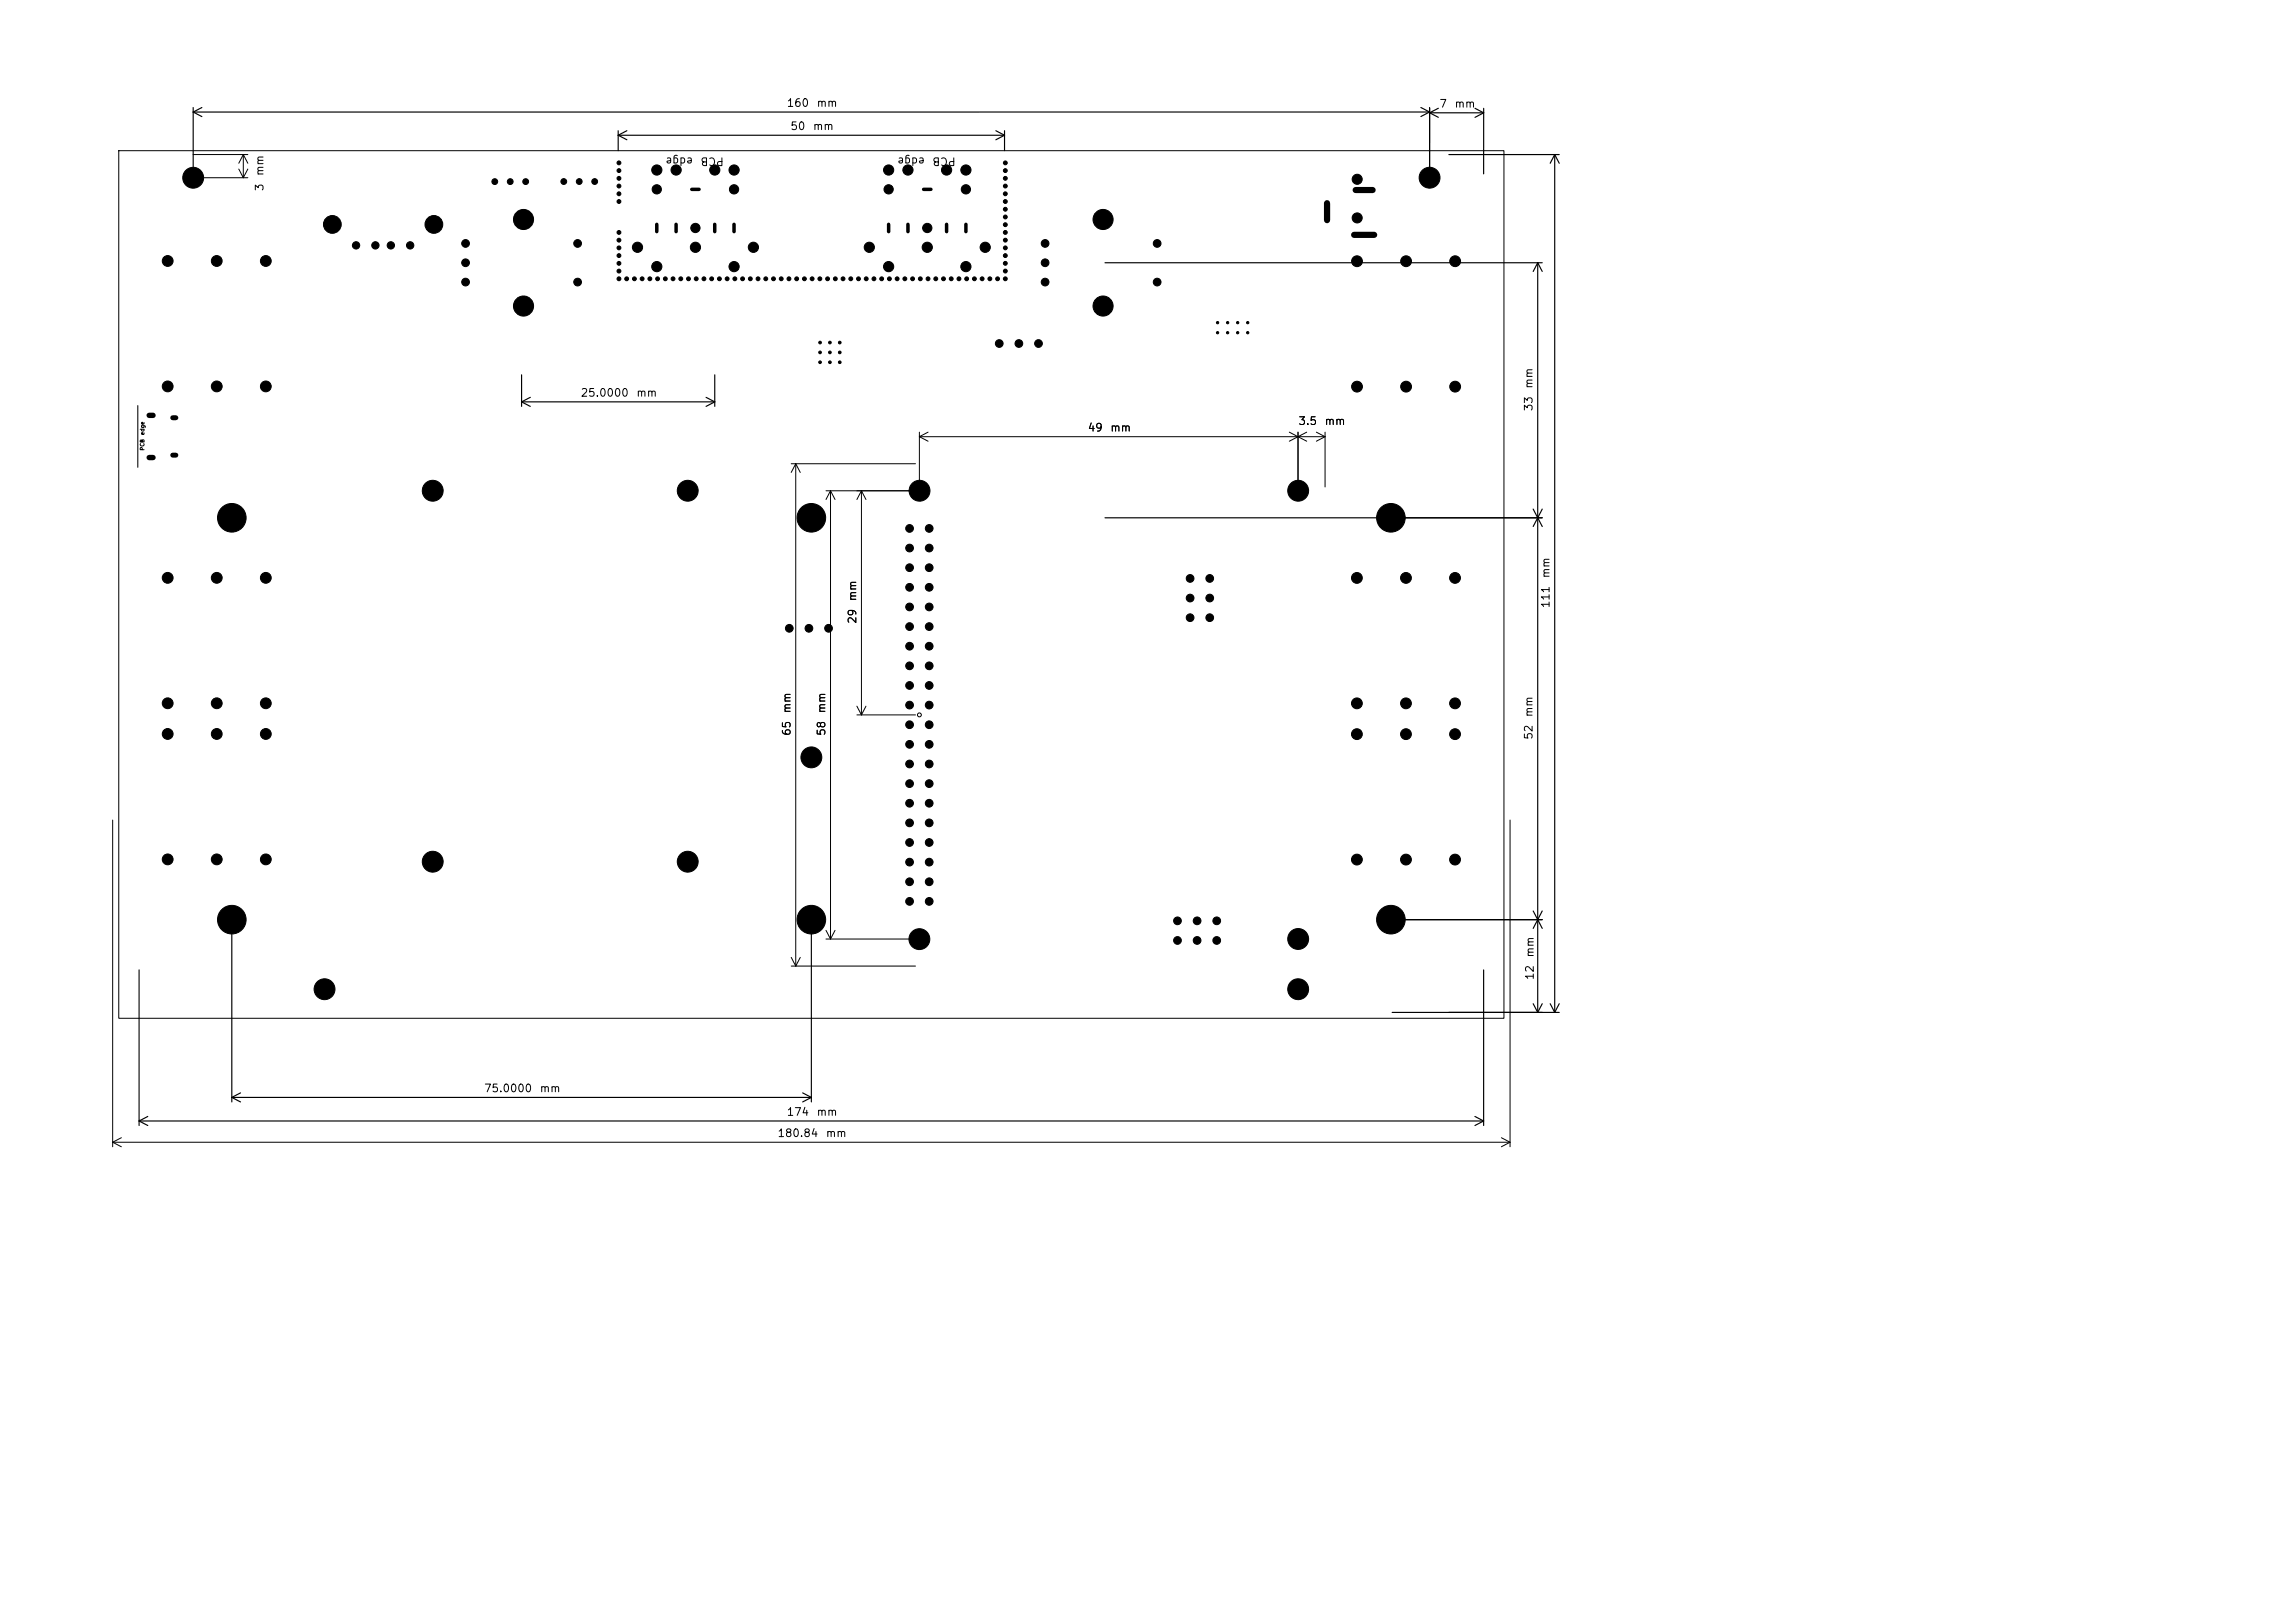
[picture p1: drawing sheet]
<svg xmlns="http://www.w3.org/2000/svg" width="297mm" height="210mm" viewBox="0 0 297 210" stroke-linecap="round" stroke-linejoin="round" font-family="sans-serif">
<defs><g id="words">
<g font-size="1">
<text x="101.7" y="14.1">160</text>
<text x="102.2" y="17.1">50</text>
<text x="105.1" y="17.1">mm</text>
<text x="105.6" y="14.1">mm</text>
<text x="186.2" y="14.2">7</text>
<text x="188.2" y="14.2">mm</text>
<text x="34.3" y="22.8" transform="rotate(-90 34.3 22.8)">mm</text>
<text x="89.8" y="20.1" transform="rotate(-180 89.8 20.1)">edge</text>
<text x="93.8" y="20.1" transform="rotate(-180 93.8 20.1)">PCB</text>
<text x="119.8" y="20.1" transform="rotate(-180 119.8 20.1)">edge</text>
<text x="123.8" y="20.1" transform="rotate(-180 123.8 20.1)">PCB</text>
<text x="34.3" y="24.8" transform="rotate(-90 34.3 24.8)">3</text>
<text x="75.1" y="51.6">25.0000</text>
<text x="82.3" y="51.6">mm</text>
<text x="198.6" y="53.3" transform="rotate(-90 198.6 53.3)">33</text>
<text x="198.6" y="50.4" transform="rotate(-90 198.6 50.4)">mm</text>
<text x="140.7" y="56.1">49</text>
<text x="143.6" y="56.1">mm</text>
<text x="168" y="55.2">3.5</text>
<text x="171.3" y="55.2">mm</text>
<text x="111.1" y="77.9" transform="rotate(-90 111.1 77.9)">mm</text>
<text x="200.8" y="74.9" transform="rotate(-90 200.8 74.9)">mm</text>
<text x="111.1" y="80.8" transform="rotate(-90 111.1 80.8)">29</text>
<text x="200.8" y="78.8" transform="rotate(-90 200.8 78.8)">111</text>
<text x="102.6" y="95.3" transform="rotate(-90 102.6 95.3)">65</text>
<text x="102.6" y="92.4" transform="rotate(-90 102.6 92.4)">mm</text>
<text x="107.1" y="95.3" transform="rotate(-90 107.1 95.3)">58</text>
<text x="107.1" y="92.4" transform="rotate(-90 107.1 92.4)">mm</text>
<text x="198.6" y="95.8" transform="rotate(-90 198.6 95.8)">52</text>
<text x="198.6" y="92.9" transform="rotate(-90 198.6 92.9)">mm</text>
<text x="198.7" y="124" transform="rotate(-90 198.7 124)">mm</text>
<text x="198.7" y="126.9" transform="rotate(-90 198.7 126.9)">12</text>
<text x="62.6" y="141.6">75.0000</text>
<text x="69.8" y="141.6">mm</text>
<text x="100.5" y="147.4">180.84</text>
<text x="101.7" y="144.6">174</text>
<text x="105.6" y="144.6">mm</text>
<text x="106.8" y="147.4">mm</text>
</g>
<g font-size=".5">
<text x="18.8" y="58.4" transform="rotate(-90 18.8 58.4)">PCB</text>
<text x="18.8" y="56.4" transform="rotate(-90 18.8 56.4)">edge</text>
</g>
</g></defs>
<g fill="none" stroke="#000" stroke-width=".13">
<path d="M15.4 19.5h179.2v112.3h-179.2zM25 20h7.1M31.5 20v3M31.5 20l.6 1.1M31.5 20l-.6 1.1M25 23h7.1M30.9 21.9l.6 1.1M32.1 21.9l-.6 1.1M17.8 52.5v8M119 55.9v7.1M119 56.5h52.5M119 56.5l1.1 .6"/>
<path d="M120.1 55.9l-1.1 .6M166.9 55.9l2.2 1.2M168 55.9v7.1M169.1 55.9l-2.2 1.2M170.4 55.9l1.1 .6M171.5 55.9v7.1M171.5 56.5l-1.1 .6M102.4 60h16.1M103 60v65M103 60l.6 1.1M103 60l-.6 1.1M106.9 63.5h11.6"/>
<path d="M107.5 63.5v58M107.5 63.5l.6 1.1M107.5 63.5l-.6 1.1M111.5 63.5v29M111.5 63.5l.6 1.1M111.5 63.5l-.6 1.1M110.9 92.5h7.6M110.9 91.4l.6 1.1M112.1 91.4l-.6 1.1M14.6 106.1v42.3M195.4 106.1v42.3M102.4 125h16.1"/>
<path d="M102.4 123.9l.6 1.1M103.6 123.9l-.6 1.1M106.9 121.5h11.6M106.9 120.4l.6 1.1M108.1 120.4l-.6 1.1M14.6 147.8h180.8M14.6 147.8l1.1 .6M15.7 147.2l-1.1 .6M194.3 147.2l1.1 .6M195.4 147.8l-1.1 .6"/>
<circle cx="119" cy="92.5" r=".25"/>
</g>
<g fill="none" stroke="#000" stroke-width=".15">
<path d="M25 13.9v8.6M25 14.5l1.1 .6M26.1 13.9l-1.1 .6M80 16.9v2.6M80 17.5h50M80 17.5l1.1 .6M81.1 16.9l-1.1 .6M128.9 16.9l1.1 .6M130 16.9v2.6M130 17.5l-1.1 .6M183.9 13.9l1.1 .6M185 13.9v8.6"/>
<path d="M185 14.5h-160M185 14.5l-1.1 .6M185 14.6h7M185 14.6l1.1 .6M186.1 14l-1.1 .6M190.9 14l1.1 .6M192 14.6l-1.1 .6M192 14v8.5M143 34h56.6M187.5 20h14.3M199 34v97M199 34l.6 1.1"/>
<path d="M199 34l-.6 1.1M201.2 20v111M201.2 20l.6 1.1M201.2 20l-.6 1.1M67.5 48.5v4.1M67.5 52h25M67.5 52l1.1 .6M68.6 51.4l-1.1 .6M91.4 51.4l1.1 .6M92.5 48.5v4.1M92.5 52l-1.1 .6M143 67h56.6"/>
<path d="M198.4 65.9l1.2 2.2M199.6 65.9l-1.2 2.2M30 119.5v23.1M105 119.5v23.1M180.2 119h19.4M198.4 117.9l1.2 2.2M199.6 117.9l-1.2 2.2M18 125.5v20.1M180.2 131h21.6M192 125.5v20.1M198.4 129.9l.6 1.1M199.6 129.9l-.6 1.1"/>
<path d="M200.6 129.9l.6 1.1M201.8 129.9l-.6 1.1M18 145.1h174M18 145.1l1.1 .5M19.1 144.5l-1.1 .6M30 142h75M30 142l1.1 .6M31.1 141.4l-1.1 .6M103.9 141.4l1.1 .6M105 142l-1.1 .6M190.9 144.5l1.1 .6M192 145.1l-1.1 .5"/>
</g>
<g fill="#000" stroke="#000" stroke-width=".13">
<circle cx="21.7" cy="33.8" r=".7"/>
<circle cx="25" cy="23" r="1.35"/>
<circle cx="28" cy="33.8" r=".7"/>
<circle cx="34.4" cy="33.8" r=".7"/>
<circle cx="43" cy="29" r="1.15"/>
<circle cx="46.1" cy="31.8" r=".47"/>
<circle cx="48.6" cy="31.8" r=".47"/>
<circle cx="50.6" cy="31.8" r=".47"/>
<circle cx="53.1" cy="31.8" r=".47"/>
<circle cx="56.1" cy="29" r="1.15"/>
<circle cx="60.2" cy="36.5" r=".5"/>
<circle cx="60.2" cy="31.5" r=".5"/>
<circle cx="60.2" cy="34" r=".5"/>
<circle cx="64" cy="23.5" r=".38"/>
<circle cx="66" cy="23.5" r=".38"/>
<circle cx="67.7" cy="28.4" r="1.3"/>
<circle cx="67.7" cy="39.6" r="1.3"/>
<circle cx="68" cy="23.5" r=".38"/>
<circle cx="73" cy="23.5" r=".37"/>
<circle cx="74.8" cy="36.5" r=".5"/>
<circle cx="74.8" cy="31.5" r=".5"/>
<circle cx="75" cy="23.5" r=".37"/>
<circle cx="77" cy="23.5" r=".37"/>
<circle cx="80.1" cy="22.1" r=".25"/>
<circle cx="80.1" cy="25.1" r=".25"/>
<circle cx="80.1" cy="23.1" r=".25"/>
<circle cx="80.1" cy="24.1" r=".25"/>
<circle cx="80.1" cy="21.1" r=".25"/>
<circle cx="80.1" cy="26.1" r=".25"/>
<circle cx="80.1" cy="32.1" r=".25"/>
<circle cx="80.1" cy="33.1" r=".25"/>
<circle cx="80.1" cy="35.1" r=".25"/>
<circle cx="80.1" cy="30.1" r=".25"/>
<circle cx="80.1" cy="34.1" r=".25"/>
<circle cx="80.1" cy="31.1" r=".25"/>
<circle cx="80.1" cy="36.1" r=".25"/>
<circle cx="81.1" cy="36.1" r=".25"/>
<circle cx="82.1" cy="36.1" r=".25"/>
<circle cx="82.5" cy="32" r=".66"/>
<circle cx="83.1" cy="36.1" r=".25"/>
<circle cx="84.1" cy="36.1" r=".25"/>
<circle cx="85" cy="24.5" r=".6"/>
<circle cx="85" cy="34.5" r=".66"/>
<circle cx="85" cy="22" r=".66"/>
<circle cx="85.1" cy="36.1" r=".25"/>
<circle cx="86.1" cy="36.1" r=".25"/>
<circle cx="87.1" cy="36.1" r=".25"/>
<circle cx="87.5" cy="22" r=".66"/>
<circle cx="88.1" cy="36.1" r=".25"/>
<circle cx="89.1" cy="36.1" r=".25"/>
<circle cx="90" cy="29.5" r=".6"/>
<circle cx="90" cy="32" r=".66"/>
<circle cx="90.1" cy="36.1" r=".25"/>
<circle cx="91.1" cy="36.1" r=".25"/>
<circle cx="92.1" cy="36.1" r=".25"/>
<circle cx="92.5" cy="22" r=".66"/>
<circle cx="93.1" cy="36.1" r=".25"/>
<circle cx="94.1" cy="36.1" r=".25"/>
<circle cx="95" cy="24.5" r=".6"/>
<circle cx="95" cy="34.5" r=".66"/>
<circle cx="95" cy="22" r=".66"/>
<circle cx="95.1" cy="36.1" r=".25"/>
<circle cx="96.1" cy="36.1" r=".25"/>
<circle cx="97.1" cy="36.1" r=".25"/>
<circle cx="97.5" cy="32" r=".66"/>
<circle cx="98.1" cy="36.1" r=".25"/>
<circle cx="99.1" cy="36.1" r=".25"/>
<circle cx="100.1" cy="36.1" r=".25"/>
<circle cx="101.1" cy="36.1" r=".25"/>
<circle cx="102.1" cy="36.1" r=".25"/>
<circle cx="103.1" cy="36.1" r=".25"/>
<circle cx="104.1" cy="36.1" r=".25"/>
<circle cx="105.1" cy="36.1" r=".25"/>
<circle cx="106.1" cy="36.1" r=".25"/>
<circle cx="107.1" cy="36.1" r=".25"/>
<circle cx="108.1" cy="36.1" r=".25"/>
<circle cx="109.1" cy="36.1" r=".25"/>
<circle cx="110.1" cy="36.1" r=".25"/>
<circle cx="111.1" cy="36.1" r=".25"/>
<circle cx="112.1" cy="36.1" r=".25"/>
<circle cx="112.5" cy="32" r=".66"/>
<circle cx="113.1" cy="36.1" r=".25"/>
<circle cx="114.1" cy="36.1" r=".25"/>
<circle cx="115" cy="34.5" r=".66"/>
<circle cx="115" cy="22" r=".66"/>
<circle cx="115" cy="24.5" r=".6"/>
<circle cx="115.1" cy="36.1" r=".25"/>
<circle cx="116.1" cy="36.1" r=".25"/>
<circle cx="117.1" cy="36.1" r=".25"/>
<circle cx="117.5" cy="22" r=".66"/>
<circle cx="118.1" cy="36.1" r=".25"/>
<circle cx="119.1" cy="36.1" r=".25"/>
<circle cx="120" cy="29.5" r=".6"/>
<circle cx="120" cy="32" r=".66"/>
<circle cx="120.1" cy="36.1" r=".25"/>
<circle cx="121.1" cy="36.1" r=".25"/>
<circle cx="122.1" cy="36.1" r=".25"/>
<circle cx="122.5" cy="22" r=".66"/>
<circle cx="123.1" cy="36.1" r=".25"/>
<circle cx="124.1" cy="36.1" r=".25"/>
<circle cx="125" cy="34.5" r=".66"/>
<circle cx="125" cy="22" r=".66"/>
<circle cx="125" cy="24.5" r=".6"/>
<circle cx="125.1" cy="36.1" r=".25"/>
<circle cx="126.1" cy="36.1" r=".25"/>
<circle cx="127.1" cy="36.1" r=".25"/>
<circle cx="127.5" cy="32" r=".66"/>
<circle cx="128.1" cy="36.1" r=".25"/>
<circle cx="129.1" cy="36.1" r=".25"/>
<circle cx="130.1" cy="28.1" r=".25"/>
<circle cx="130.1" cy="27.1" r=".25"/>
<circle cx="130.1" cy="22.1" r=".25"/>
<circle cx="130.1" cy="25.1" r=".25"/>
<circle cx="130.1" cy="23.1" r=".25"/>
<circle cx="130.1" cy="24.1" r=".25"/>
<circle cx="130.1" cy="26.1" r=".25"/>
<circle cx="130.1" cy="21.1" r=".25"/>
<circle cx="130.1" cy="32.1" r=".25"/>
<circle cx="130.1" cy="35.1" r=".25"/>
<circle cx="130.1" cy="33.1" r=".25"/>
<circle cx="130.1" cy="30.1" r=".25"/>
<circle cx="130.1" cy="34.1" r=".25"/>
<circle cx="130.1" cy="29.1" r=".25"/>
<circle cx="130.1" cy="36.1" r=".25"/>
<circle cx="130.1" cy="31.1" r=".25"/>
<circle cx="135.3" cy="36.5" r=".5"/>
<circle cx="135.3" cy="31.5" r=".5"/>
<circle cx="135.3" cy="34" r=".5"/>
<circle cx="142.8" cy="28.4" r="1.3"/>
<circle cx="142.8" cy="39.6" r="1.3"/>
<circle cx="149.7" cy="31.5" r=".5"/>
<circle cx="149.7" cy="36.5" r=".5"/>
<circle cx="175.6" cy="33.8" r=".7"/>
<circle cx="175.6" cy="23.2" r=".65"/>
<circle cx="175.6" cy="28.2" r=".65"/>
<circle cx="182" cy="33.8" r=".7"/>
<circle cx="185" cy="23" r="1.35"/>
<circle cx="188.3" cy="33.8" r=".7"/>
<circle cx="21.7" cy="50" r=".7"/>
<circle cx="28" cy="50" r=".7"/>
<circle cx="34.4" cy="50" r=".7"/>
<circle cx="106.1" cy="46.9" r=".17"/>
<circle cx="106.1" cy="44.3" r=".17"/>
<circle cx="106.1" cy="45.6" r=".17"/>
<circle cx="107.4" cy="46.9" r=".17"/>
<circle cx="107.4" cy="45.6" r=".17"/>
<circle cx="107.4" cy="44.3" r=".17"/>
<circle cx="108.7" cy="46.9" r=".17"/>
<circle cx="108.7" cy="44.3" r=".17"/>
<circle cx="108.7" cy="45.6" r=".17"/>
<circle cx="129.3" cy="44.5" r=".5"/>
<circle cx="131.9" cy="44.5" r=".5"/>
<circle cx="134.4" cy="44.5" r=".5"/>
<circle cx="157.6" cy="41.8" r=".15"/>
<circle cx="157.6" cy="43.1" r=".15"/>
<circle cx="158.9" cy="43.1" r=".15"/>
<circle cx="158.9" cy="41.8" r=".15"/>
<circle cx="160.2" cy="43.1" r=".15"/>
<circle cx="160.2" cy="41.8" r=".15"/>
<circle cx="161.5" cy="43.1" r=".15"/>
<circle cx="161.5" cy="41.8" r=".15"/>
<circle cx="175.6" cy="50" r=".7"/>
<circle cx="182" cy="50" r=".7"/>
<circle cx="188.3" cy="50" r=".7"/>
<circle cx="21.7" cy="74.8" r=".7"/>
<circle cx="28" cy="74.8" r=".7"/>
<circle cx="30" cy="67" r="1.85"/>
<circle cx="34.4" cy="74.8" r=".7"/>
<circle cx="56" cy="63.5" r="1.35"/>
<circle cx="89" cy="63.5" r="1.35"/>
<circle cx="105" cy="67" r="1.85"/>
<circle cx="117.7" cy="70.9" r=".5"/>
<circle cx="117.7" cy="78.5" r=".5"/>
<circle cx="117.7" cy="76" r=".5"/>
<circle cx="117.7" cy="68.4" r=".5"/>
<circle cx="117.7" cy="73.5" r=".5"/>
<circle cx="119" cy="63.5" r="1.35"/>
<circle cx="120.3" cy="68.4" r=".5"/>
<circle cx="120.3" cy="78.5" r=".5"/>
<circle cx="120.3" cy="70.9" r=".5"/>
<circle cx="120.3" cy="73.5" r=".5"/>
<circle cx="120.3" cy="76" r=".5"/>
<circle cx="154" cy="74.8" r=".5"/>
<circle cx="154" cy="77.4" r=".5"/>
<circle cx="154" cy="79.9" r=".5"/>
<circle cx="156.6" cy="74.8" r=".5"/>
<circle cx="156.6" cy="77.4" r=".5"/>
<circle cx="156.6" cy="79.9" r=".5"/>
<circle cx="168" cy="63.5" r="1.35"/>
<circle cx="175.6" cy="74.8" r=".7"/>
<circle cx="180" cy="67" r="1.85"/>
<circle cx="181.9" cy="74.8" r=".7"/>
<circle cx="188.3" cy="74.8" r=".7"/>
<circle cx="21.7" cy="95" r=".7"/>
<circle cx="21.7" cy="91" r=".7"/>
<circle cx="28" cy="95" r=".7"/>
<circle cx="28" cy="91" r=".7"/>
<circle cx="34.4" cy="95" r=".7"/>
<circle cx="34.4" cy="91" r=".7"/>
<circle cx="102.1" cy="81.3" r=".5"/>
<circle cx="104.7" cy="81.3" r=".5"/>
<circle cx="105" cy="98" r="1.35"/>
<circle cx="107.2" cy="81.3" r=".5"/>
<circle cx="117.7" cy="83.6" r=".5"/>
<circle cx="117.7" cy="93.8" r=".5"/>
<circle cx="117.7" cy="86.2" r=".5"/>
<circle cx="117.7" cy="91.2" r=".5"/>
<circle cx="117.7" cy="98.9" r=".5"/>
<circle cx="117.7" cy="81.1" r=".5"/>
<circle cx="117.7" cy="96.3" r=".5"/>
<circle cx="117.7" cy="88.7" r=".5"/>
<circle cx="120.3" cy="96.3" r=".5"/>
<circle cx="120.3" cy="93.8" r=".5"/>
<circle cx="120.3" cy="81.1" r=".5"/>
<circle cx="120.3" cy="83.6" r=".5"/>
<circle cx="120.3" cy="86.2" r=".5"/>
<circle cx="120.3" cy="88.7" r=".5"/>
<circle cx="120.3" cy="98.9" r=".5"/>
<circle cx="120.3" cy="91.2" r=".5"/>
<circle cx="175.6" cy="91" r=".7"/>
<circle cx="175.6" cy="95" r=".7"/>
<circle cx="181.9" cy="91" r=".7"/>
<circle cx="181.9" cy="95" r=".7"/>
<circle cx="188.3" cy="91" r=".7"/>
<circle cx="188.3" cy="95" r=".7"/>
<circle cx="21.7" cy="111.2" r=".7"/>
<circle cx="28" cy="111.2" r=".7"/>
<circle cx="30" cy="119" r="1.85"/>
<circle cx="34.4" cy="111.2" r=".7"/>
<circle cx="56" cy="111.5" r="1.35"/>
<circle cx="89" cy="111.5" r="1.35"/>
<circle cx="105" cy="119" r="1.85"/>
<circle cx="117.7" cy="114.1" r=".5"/>
<circle cx="117.7" cy="103.9" r=".5"/>
<circle cx="117.7" cy="101.4" r=".5"/>
<circle cx="117.7" cy="116.6" r=".5"/>
<circle cx="117.7" cy="106.5" r=".5"/>
<circle cx="117.7" cy="109" r=".5"/>
<circle cx="117.7" cy="111.6" r=".5"/>
<circle cx="120.3" cy="103.9" r=".5"/>
<circle cx="120.3" cy="111.6" r=".5"/>
<circle cx="120.3" cy="101.4" r=".5"/>
<circle cx="120.3" cy="109" r=".5"/>
<circle cx="120.3" cy="116.6" r=".5"/>
<circle cx="120.3" cy="106.5" r=".5"/>
<circle cx="120.3" cy="114.1" r=".5"/>
<circle cx="152.4" cy="119.2" r=".5"/>
<circle cx="154.9" cy="119.2" r=".5"/>
<circle cx="157.5" cy="119.2" r=".5"/>
<circle cx="175.6" cy="111.2" r=".7"/>
<circle cx="180" cy="119" r="1.85"/>
<circle cx="181.9" cy="111.2" r=".7"/>
<circle cx="188.3" cy="111.2" r=".7"/>
<circle cx="42" cy="128" r="1.35"/>
<circle cx="119" cy="121.5" r="1.35"/>
<circle cx="152.4" cy="121.7" r=".5"/>
<circle cx="154.9" cy="121.7" r=".5"/>
<circle cx="157.5" cy="121.7" r=".5"/>
<circle cx="168" cy="121.5" r="1.35"/>
<circle cx="168" cy="128" r="1.35"/>
</g>
<path d="M85 29v1M87.5 29v1M89.5 24.5h1M92.5 29v1M95 29v1M115 29v1M117.5 29v1M119.5 24.5h1M122.5 29v1M125 29v1" fill="none" stroke="#000" stroke-width=".45"/>
<path d="M171.7 26.3v2.2M175.2 30.4h2.6M175.4 24.6h2.2" fill="none" stroke="#000" stroke-width=".8"/>
<path d="M19.3 53.7h.5M19.3 59.2h.5" fill="none" stroke="#000" stroke-width=".7"/>
<path d="M22.4 54.1h.4M22.4 58.9h.4" fill="none" stroke="#000" stroke-width=".65"/>
<use href="#words"/>
</svg>
